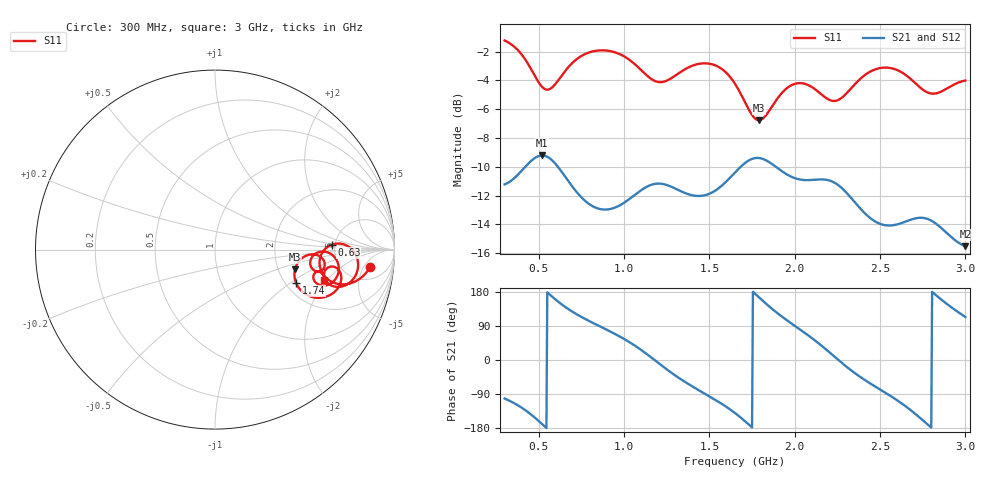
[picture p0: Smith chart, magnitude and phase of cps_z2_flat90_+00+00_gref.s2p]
! cps_z2_flat90_+00+00_gref
! simulated by sim/fixtures_fdtd.py (S12 = S21, S22 not computed)
# HZ S RI R 50
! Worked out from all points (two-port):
!   541 points, 300 MHz to 3 GHz, reference 50 ohm
!   highest |S21| = -9.21 dB at 520 MHz (marker M1); lowest = -15.5 dB at 3 GHz (marker M2)
!   |S21| within 3 dB of the highest: start of sweep to 757.3 MHz; 1.034 GHz to 2.334 GHz (1.299 GHz wide, 77.2 % of centre)
!   lowest |S11| = -6.8 dB at 1.79 GHz (marker M3), VSWR 2.70, Z = 124 - j34.3 ohm
!   |S11| at or under -10 dB: nowhere
!   |S22| runs from - to - dB; largest |S21 - S12| = 0
!   S11 on the Smith chart (normalised r, x): 300 MHz: 9, -7; 630 MHz: 4.67, +0.44; 1.74 GHz: 2.27, -1.11; 3 GHz: 3.31, -1.84
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3e8  0.8633 -0.0987  -0.0554 -0.269  -0.0554 -0.269  0 0
4.25e8  0.7141 -0.1939  -0.219 -0.2305  -0.219 -0.2305  0 0
5.2e8  0.5888 -0.1108  -0.34 -0.0652  -0.34 -0.0652  0 0
6.3e8  0.6496 0.0271  -0.2604 0.161  -0.2604 0.161  0 0
7.5e8  0.7673 -0.00311  -0.0994 0.2267  -0.0994 0.2267  0 0
8.85e8  0.7946 -0.1119  0.0278 0.2227  0.0278 0.2227  0 0
1.025e9  0.7211 -0.201  0.1597 0.1828  0.1597 0.1828  0 0
1.2e9  0.6073 -0.1395  0.274 -0.0359  0.274 -0.0359  0 0
1.4e9  0.698 -0.1282  0.0875 -0.2359  0.0875 -0.2359  0 0
1.525e9  0.6803 -0.2206  -0.056 -0.2531  -0.056 -0.2531  0 0
1.65e9  0.5533 -0.2666  -0.2312 -0.1941  -0.2312 -0.1941  0 0
1.74e9  0.452 -0.1861  -0.3329 -0.0353  -0.3329 -0.0353  0 0
1.79e9  0.4458 -0.1094  -0.3283 0.085  -0.3283 0.085  0 0
1.925e9  0.5702 -0.031  -0.1266 0.2776  -0.1266 0.2776  0 0
2.1e9  0.5865 -0.1198  0.151 0.2411  0.151 0.2411  0 0
2.26e9  0.5396 -0.043  0.2714 -0.0076  0.2714 -0.0076  0 0
2.38e9  0.6355 -0.0187  0.1653 -0.1568  0.1653 -0.1568  0 0
2.55e9  0.6843 -0.1393  -0.00583 -0.1975  -0.00583 -0.1975  0 0
2.67e9  0.6135 -0.2001  -0.1297 -0.16  -0.1297 -0.16  0 0
2.78e9  0.5488 -0.1628  -0.2052 -0.0343  -0.2052 -0.0343  0 0
2.885e9  0.5753 -0.1235  -0.1625 0.0933  -0.1625 0.0933  0 0
3e9  0.6076 -0.1674  -0.0666 0.1536  -0.0666 0.1536  0 0
